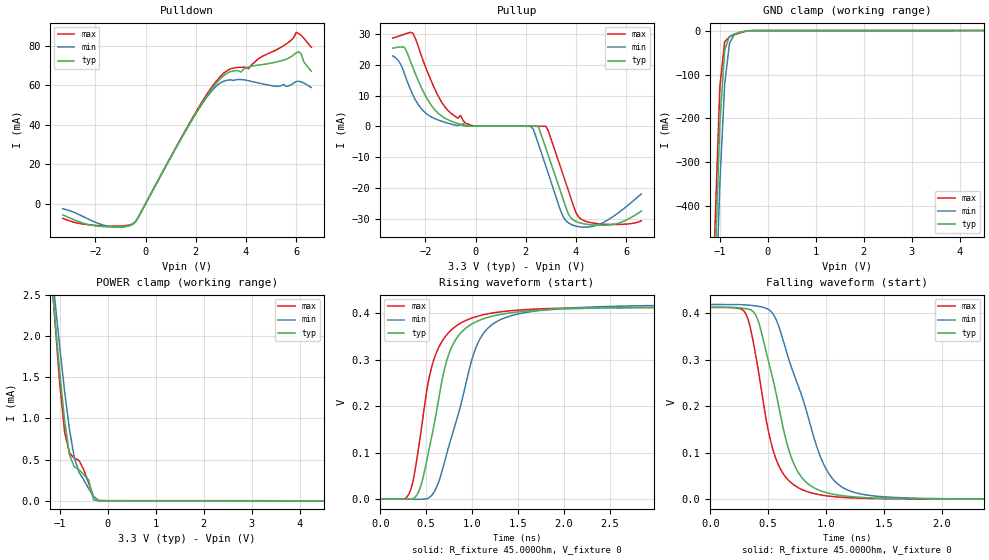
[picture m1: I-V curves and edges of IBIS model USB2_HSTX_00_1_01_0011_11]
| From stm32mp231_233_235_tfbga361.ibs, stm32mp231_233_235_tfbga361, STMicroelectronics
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[Model] USB2_HSTX_00_1_01_0011_11
Model_type   Output
Polarity   Non-Inverting
Enable   Active-High
C_comp   8.036pF   7.631pF   8.569pF
Vmeas = 200.000mV
Vref = 200.000mV
Rref = 45Ohms
Cref = 0pF
[Model Spec]
Vmeas   200.000mV   200.000mV   200.000mV
Vref   200.000mV   200.000mV   200.000mV
| This model is not intended for timing simulations.
| Warnings about Cref, Vref & Rref can be ignored
[Temperature Range]   25.000   125.000   -40.000
[Voltage Range]   3.300V   3.070V   3.630V
[GND Clamp Reference]   0.00V   0.00V   0.00V
[Pulldown Reference]   0.00V   0.00V   0.00V
[POWER Clamp Reference]   3.300V   3.070V   3.630V
[Pullup Reference]   3.300V   3.070V   3.630V
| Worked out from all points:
|   slope of the pulldown table from 0 to 0.495 V, typ, clamps not added: 42.6 ohm
|   GND clamp passes 1 mA (typ) near -0.43 V on its own axis
|   POWER clamp passes 1 mA (typ) near -0.91 V on its own axis
|   rising waveform, R_fixture 45.000Ohm, V_fixture 0: 20-80 % time 279ps typ, 356ps min, 250ps max; typ from 0 V to 0.413 V
|   falling waveform, R_fixture 45.000Ohm, V_fixture 0: 20-80 % time 241ps typ, 327ps min, 196ps max; typ from 0.413 V to 0 V
[GND Clamp]
-3.3V     -11.02A    -10.62A    -11.32A
-1.2V     -931.6mA   -1.049A    -855.7mA
-1.1V     -533.1mA   -671.7mA   -440.2mA
-1V       -209.4mA   -347mA     -127.3mA
-900mV    -44.44mA   -121.7mA   -25.6mA
-800mV    -13.15mA   -29.48mA   -14.15mA
-700mV    -7.742mA   -9.125mA   -9.769mA
-500mV    -2.127mA   -1.981mA   -2.894mA
-300mV    -19.36uA   -62.22uA   -13.54uA
6.6V      10.37uA    26.59uA    21.05uA
[Power Clamp]
-3.3V     3.206A     2.175A     4.855A
-1.2V     2.88mA     3.008mA    2.969mA
-1.1V     2.195mA    2.419mA    2.156mA
-1V       1.545mA    1.852mA    1.406mA
-900mV    967.9uA    1.324mA    831.4uA
-800mV    558.5uA    864.6uA    580.3uA
-700mV    412uA      525.9uA    517uA
-600mV    376.6uA    345uA      488.5uA
-400mV    254.2uA    146.6uA    216.8uA
-300mV    11.21uA    52.87uA    53.51uA
-100mV    94.79nA    985nA      361.1nA
6.6V      -3.252uA   -5.18uA    -3.94uA
[Pulldown]
-3.3V     -5.671mA   -2.581mA   -7.449mA
-1.6V     -11.64mA   -11.09mA   -11.31mA
-500mV    -10.25mA   -10.32mA   -10.1mA
1.9V      43.42mA    43.46mA    44.13mA
2.9V      62.15mA    60.37mA    63.26mA
3.4V      66.87mA    62.63mA    68.29mA
4.1V      69.19mA    62.19mA    68.26mA
4.5V      70.11mA    61.06mA    73.4mA
5.6V      73.12mA    59.29mA    80.76mA
6V        76.33mA    61.79mA    86.69mA
6.1V      76.87mA    61.92mA    85.99mA
6.6V      66.99mA    58.79mA    79.1mA
[Pullup]
-3.3V     25.41mA    22.86mA    28.67mA
-2.8V     25.3mA     16.38mA    30mA
-2.5V     19.22mA    10.28mA    30.28mA
-1.2V     2.602mA    1.31mA     6.11mA
-100mV    93.8uA     82.61uA    220.4uA
2.2V      68.59uA    -28.24uA   104.8uA
2.5V      -41.41uA   -5.658mA   83.48uA
2.9V      -9.472mA   -15.37mA   -1.562mA
3.5V      -23.92mA   -29.44mA   -16.02mA
3.8V      -29.68mA   -31.75mA   -23.35mA
4.4V      -31.68mA   -32.65mA   -30.79mA
6.6V      -27.44mA   -21.87mA   -30.62mA
[Ramp]
R_load=45.000Ohm
dV/dt_r   624.180mV/1.120ns  592.511mV/1.160ns  677.764mV/1.040ns
dV/dt_f   626.380mV/265.000ps  595.435mV/350.000ps  679.593mV/225.000ps
[Rising waveform]
R_fixture=45.000Ohm
V_fixture=0
0s        452.1nV    3.129uV    468.1nV
330ps     -200.2uV   -412.7uV   19.76mV
440ps     27.58mV    -306.8uV   140.7mV
580ps     153.8mV    13.3mV     298.1mV
780ps     328.2mV    136.1mV    365.5mV
1.01ns    378.6mV    308.3mV    390.9mV
1.14ns    389.5mV    360.9mV    397.8mV
1.51ns    403.4mV    399.1mV    407.2mV
2.38ns    411.4mV    414.3mV    412.4mV
9.9ns     413.1mV    419.2mV    412.9mV
[Falling waveform]
R_fixture=45.000Ohm
V_fixture=0
0s        412.6mV    418.6mV    412.3mV
310ps     409.6mV    417.6mV    396.7mV
410ps     385.7mV    414.9mV    283.8mV
540ps     258.8mV    398.9mV    107.3mV
650ps     130.9mV    323.5mV    48mV
720ps     76.94mV    269.7mV    31.23mV
960ps     17.56mV    85.72mV    9.103mV
1.17ns    6.864mV    21.76mV    3.734mV
1.65ns    1.442mV    3.396mV    968.9uV
9.9ns     13.76uV    30.59uV    4.187uV
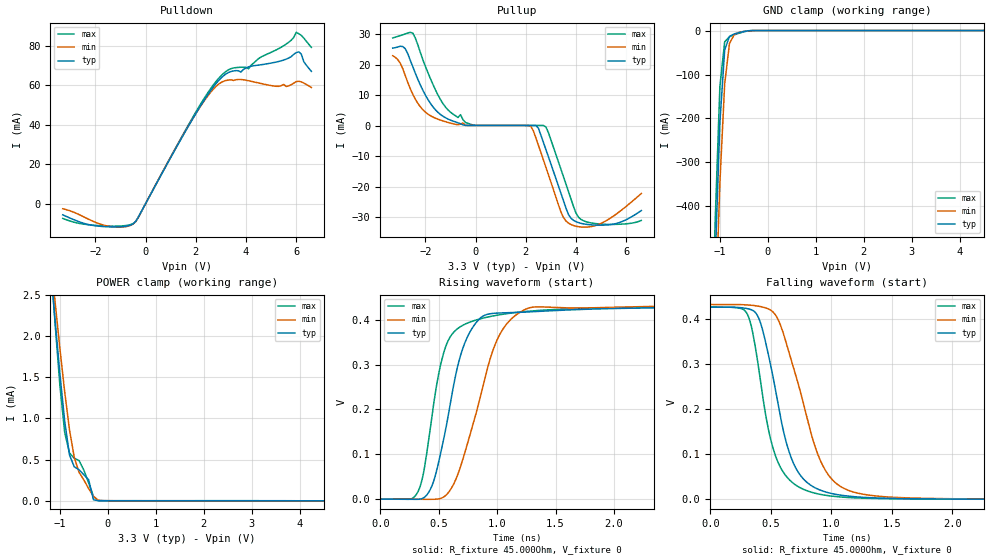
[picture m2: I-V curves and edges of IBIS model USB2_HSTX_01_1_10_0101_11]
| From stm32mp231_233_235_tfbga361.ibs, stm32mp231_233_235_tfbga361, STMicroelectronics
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[Model] USB2_HSTX_01_1_10_0101_11
Model_type   Output
Polarity   Non-Inverting
Enable   Active-High
C_comp   8.036pF   7.631pF   8.569pF
Vmeas = 200.000mV
Vref = 200.000mV
Rref = 45Ohms
Cref = 0pF
[Model Spec]
Vmeas   200.000mV   200.000mV   200.000mV
Vref   200.000mV   200.000mV   200.000mV
| This model is not intended for timing simulations.
| Warnings about Cref, Vref & Rref can be ignored
[Temperature Range]   25.000   125.000   -40.000
[Voltage Range]   3.300V   3.070V   3.630V
[GND Clamp Reference]   0.00V   0.00V   0.00V
[Pulldown Reference]   0.00V   0.00V   0.00V
[POWER Clamp Reference]   3.300V   3.070V   3.630V
[Pullup Reference]   3.300V   3.070V   3.630V
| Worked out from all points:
|   slope of the pulldown table from 0 to 0.495 V, typ, clamps not added: 42.6 ohm
|   GND clamp passes 1 mA (typ) near -0.43 V on its own axis
|   POWER clamp passes 1 mA (typ) near -0.91 V on its own axis
|   rising waveform, R_fixture 45.000Ohm, V_fixture 0: 20-80 % time 213ps typ, 282ps min, 175ps max; typ from 0 V to 0.428 V
|   falling waveform, R_fixture 45.000Ohm, V_fixture 0: 20-80 % time 215ps typ, 280ps min, 185ps max; typ from 0.427 V to 0 V
[GND Clamp]
-3.3V     -11.02A    -10.62A    -11.32A
-1.2V     -931.6mA   -1.049A    -855.7mA
-1.1V     -533.1mA   -671.7mA   -440.2mA
-1V       -209.4mA   -347mA     -127.3mA
-900mV    -44.44mA   -121.7mA   -25.6mA
-800mV    -13.15mA   -29.48mA   -14.15mA
-700mV    -7.743mA   -9.125mA   -9.769mA
-500mV    -2.127mA   -1.981mA   -2.894mA
-300mV    -19.51uA   -62.22uA   -13.7uA
6.6V      10.37uA    26.59uA    21.05uA
[Power Clamp]
-3.3V     3.206A     2.175A     4.855A
-1.2V     2.88mA     3.008mA    2.969mA
-1.1V     2.195mA    2.419mA    2.156mA
-1V       1.545mA    1.852mA    1.406mA
-900mV    967.6uA    1.324mA    831.4uA
-800mV    558uA      864.6uA    580.3uA
-700mV    412uA      525.9uA    517uA
-600mV    376.6uA    345uA      488.5uA
-400mV    254.2uA    146.6uA    216.8uA
-300mV    11.21uA    52.87uA    53.51uA
-100mV    94.86nA    985nA      361.1nA
6.6V      -2.538uA   -5.181uA   -3.292uA
[Pulldown]
-3.3V     -5.671mA   -2.581mA   -7.449mA
-1.6V     -11.64mA   -11.09mA   -11.31mA
-500mV    -10.25mA   -10.32mA   -10.1mA
1.9V      43.42mA    43.46mA    44.13mA
2.9V      62.15mA    60.37mA    63.26mA
3.4V      66.87mA    62.63mA    68.29mA
4.1V      69.19mA    62.19mA    68.26mA
4.5V      70.11mA    61.06mA    73.4mA
5.6V      73.12mA    59.29mA    80.76mA
6V        76.42mA    61.78mA    86.69mA
6.1V      76.81mA    61.92mA    85.99mA
6.6V      66.95mA    58.79mA    79.1mA
[Pullup]
-3.3V     25.37mA    22.87mA    28.68mA
-2.8V     25.17mA    16.38mA    30mA
-2.5V     19.29mA    10.28mA    30.28mA
-1.7V     6.185mA    2.83mA     13.54mA
-400mV    111.7uA    77.66uA    1.021mA
2.2V      68.64uA    -248.9uA   104.8uA
2.5V      -771uA     -6.354mA   83.49uA
2.8V      -7.784mA   -13.58mA   -409.6uA
3.4V      -22.12mA   -28.2mA    -14.26mA
3.8V      -30.28mA   -32.32mA   -24mA
4.4V      -32.24mA   -33.17mA   -31.39mA
6.6V      -27.75mA   -22.18mA   -30.98mA
[Ramp]
R_load=45.000Ohm
dV/dt_r   628.630mV/1.040ns  596.900mV/1.070ns  682.278mV/975.000ps
dV/dt_f   630.819mV/240.000ps  599.812mV/315.000ps  684.093mV/215.000ps
[Rising waveform]
R_fixture=45.000Ohm
V_fixture=0
0s        452.1nV    3.134uV    468nV
330ps     -314.7uV   -409uV     20.75mV
450ps     34.96mV    -426uV     199.2mV
520ps     106.6mV    1.896mV    303.6mV
590ps     198.7mV    17.05mV    357.8mV
730ps     352.3mV    109.3mV    390.5mV
940ps     413.1mV    312.6mV    406.9mV
1.09ns    415.3mV    393mV      413.6mV
1.33ns    418mV      428.4mV    420mV
9.9ns     427.9mV    433.7mV    427.8mV
[Falling waveform]
R_fixture=45.000Ohm
V_fixture=0
0s        427.4mV    433.2mV    427.3mV
310ps     423.7mV    432.1mV    409.5mV
410ps     396.3mV    428.9mV    273mV
540ps     241.5mV    409.4mV    95.77mV
620ps     134.7mV    354.7mV    53.93mV
700ps     73.04mV    281.9mV    32.9mV
950ps     16.63mV    65.01mV    9.092mV
1.17ns    6.339mV    17.32mV    3.566mV
1.69ns    1.222mV    2.704mV    870.2uV
9.9ns     14.12uV    30.82uV    4.572uV
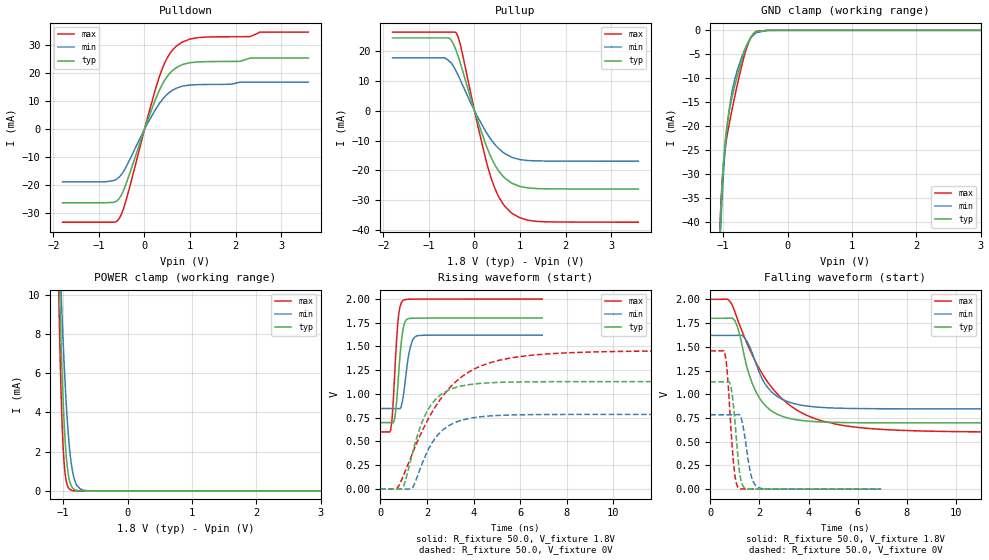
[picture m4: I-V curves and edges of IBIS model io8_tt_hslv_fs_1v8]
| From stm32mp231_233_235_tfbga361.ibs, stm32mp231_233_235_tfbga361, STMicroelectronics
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[Model]   io8_tt_hslv_fs_1v8
Model_type I/O
Polarity   Non-Inverting
Enable   Active-Low
| CAP_THRESHOLD on pad IOTT is "UDTCAPC" :
| Rising=30.0% of vddiov33m   Falling=70.0% of vddiov33m
| C_comp min and max val. don't necessarily correlate with the min and max pvt
| but are the smallest and greatest pad capacitance found.
| var   typ   min   max
C_comp   1.26692pF  1.09322pF  1.36434pF
|C_comp_pullup   869.30500fF  531.82500fF  521.20000fF
|C_comp_pulldown   397.61901fF  561.39543fF  843.14018fF
Vinl = 810.0mV
Vinh = 1.0V
Vmeas = 900.0mV   | Reference voltage for timing measurements
Cref  = 50.0pF   | Timing specification test load capacitance value
Rref  = 1.0MOhm   | Timing specification test load resistance value
Vref  = 990.0mV   | Timing specification test load voltage
[Model Spec]
| TIME_THRESHOLD on pin ZIV08M is "CMOS" :
| Rising=50.0% of vddv08m   Falling=50.0% of vddv08m
Vinl 675.70000mV 623.70000mV 735.70000mV
Vinh 1.12730V 1.01130V 1.24930V
| variable   typ   min   max
[Temperature Range] 25.0 125.0 -40.0
| variable   typ   min   max
[Voltage Range] 1.8V 1.62V 2.0V
| variable   typ   min   max
[POWER Clamp Reference] 1.8V 1.62V 2.0V
| variable   typ   min   max
[GND Clamp Reference] 0V 0V 0V
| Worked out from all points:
|   slope of the pulldown table from 0 to 0.27 V, typ, clamps not added: 22.9 ohm
|   slope of the pullup table from 0 to 0.27 V, typ, clamps not added: 22.2 ohm
|   GND clamp passes 1 mA (typ) near -0.55 V on its own axis
|   POWER clamp passes 1 mA (typ) near -0.93 V on its own axis
|   rising waveform, R_fixture 50.0, V_fixture 1.8V: 20-80 % time 218ps typ, 263ps min, 198ps max; typ from 0.698 V to 1.8 V
|   falling waveform, R_fixture 50.0, V_fixture 1.8V: 20-80 % time 878ps typ, 941ps min, 2.05ns max; typ from 1.8 V to 0.698 V
|   rising waveform, R_fixture 50.0, V_fixture 0V: 20-80 % time 1.01ns typ, 1.09ns min, 2.17ns max; typ from 0 V to 1.13 V
|   falling waveform, R_fixture 50.0, V_fixture 0V: 20-80 % time 237ps typ, 289ps min, 231ps max; typ from 1.13 V to 0 V
[POWER Clamp]
-1.8V     152.1mA    105.6mA    221.1mA
-1.07V    12.07mA    13.62mA    10.38mA
-1.05V    9.569mA    11.75mA    7.249mA
-1.03V    7.339mA    9.993mA    4.743mA
-1.01V    5.42mA     8.357mA    2.898mA
-990mV    3.841mA    6.859mA    1.662mA
-970mV    2.609mA    5.513mA    906.5uA
-940mV    1.358mA    3.806mA    344.1uA
-880mV    308.3uA    1.548mA    45.55uA
-790mV    28.47uA    298.6uA    2.144uA
-610mV    219.5nA    7.365uA    27.8nA
3.6V      0A         0A         0A
[GND Clamp]
-1.8V     -1.222A    -1.193A    -1.238A
-1.05V    -42.33mA   -45.55mA   -41.2mA
-1.04V    -38.89mA   -42.1mA    -37.88mA
-1.03V    -35.83mA   -38.98mA   -35.06mA
-1.01V    -30.7mA    -33.54mA   -30.61mA
-970mV    -23.47mA   -25.17mA   -24.97mA
-920mV    -18.06mA   -18.06mA   -20.63mA
-870mV    -14.51mA   -13.44mA   -17.13mA
-780mV    -9.532mA   -8.354mA   -11.38mA
-650mV    -3.743mA   -3.581mA   -4.327mA
-490mV    -324.1uA   -556uA     -259.6uA
3.6V      67.14nA    3.404uA    33.72nA
| variable   typ   min   max
[Pullup Reference] 1.8V 1.62V 2.0V
| variable   typ   min   max
[Pulldown Reference] 0V 0V 0V
[Pullup]
-1.8V     24.41mA    17.74mA    26.36mA
-680mV    24.41mA    17.73mA    26.36mA
-550mV    24.31mA    16.53mA    26.36mA
-400mV    20.04mA    13.14mA    26mA
-300mV    15.41mA    9.911mA    21.43mA
70mV      -3.39mA    -2.114mA   -4.868mA
340mV     -14.76mA   -9.139mA   -21.3mA
540mV     -20.33mA   -12.79mA   -29.04mA
810mV     -24.17mA   -15.52mA   -34.21mA
1V        -25.38mA   -16.37mA   -35.89mA
1.37V     -26.08mA   -16.81mA   -37.09mA
3.6V      -26.24mA   -16.92mA   -37.35mA
[Pulldown]
-1.8V     -26.25mA   -18.79mA   -33.2mA
-690mV    -26.13mA   -18.35mA   -33.2mA
-550mV    -24.6mA    -16.98mA   -31.75mA
-400mV    -19.26mA   -13.29mA   -25.07mA
70mV      3.286mA    2.202mA    4.389mA
320mV     13.66mA    9.041mA    18.43mA
500mV     18.91mA    12.52mA    25.54mA
700mV     22.05mA    14.7mA     29.73mA
1.18V     24.11mA    15.98mA    32.81mA
2.31V     25.4mA     16.88mA    33.16mA
2.54V     25.49mA    16.88mA    34.76mA
3.6V      25.49mA    16.88mA    34.76mA
[Ramp]
dV/dt_r 677.91633mV/1.00938ns 470.5214mV/1.08628ns 874.05215mV/2.1718ns
dV/dt_f 661.09817mV/874.73173ps 464.2591mV/938.08372ps 840.44947mV/2.05095ns
R_load = 50.0
| Removed startup time: 0s 0s 0s  .
| Removed end time: 6.95ns.
[Rising Waveform]
R_fixture   = 50.0
V_fixture   = 1.8V
V_fixture_min = 1.62V
V_fixture_max = 2.0V
0s        698.2mV    846.2mV    599.3mV
450ps     698.2mV    846.2mV    624.4mV
500ps     698.4mV    846.2mV    723.5mV
600ps     718.7mV    846.2mV    1.125V
750ps     1.074V     846.5mV    1.741V
850ps     1.416V     844.2mV    1.922V
1ns       1.71V      999.7mV    1.988V
1.25ns    1.796V     1.451V     1.998V
1.55ns    1.799V     1.61V      1.999V
6.95ns    1.8V       1.62V      2V
| Removed startup time: 0s 0s 0s  .
| Removed end time: 199.9ns.
[Falling Waveform]
R_fixture   = 50.0
V_fixture   = 1.8V
V_fixture_min = 1.62V
V_fixture_max = 2.0V
0s        1.8V       1.62V      2V
700ps     1.8V       1.62V      2.002V
1ns       1.774V     1.62V      1.87V
1.4ns     1.382V     1.593V     1.595V
1.8ns     1.057V     1.367V     1.364V
2.2ns     892.4mV    1.12V      1.18V
2.7ns     792.7mV    981.2mV    1.011V
4.7ns     706.3mV    858.5mV    708.5mV
8.6ns     698.3mV    846.4mV    612.9mV
199.9ns   698.2mV    846.2mV    599.3mV
| Removed startup time: 0s 0s 0s  .
| Removed end time: 199.9ns.
[Rising Waveform]
R_fixture   = 50.0
V_fixture   = 0V
V_fixture_min = 0V
V_fixture_max = 0V
0s        168.1nV    2.512uV    244.7nV
700ps     -3.16mV    -6.378uV   -1.166mV
1ns       26.06mV    -2.115mV   142.9mV
1.4ns     393.8mV    14.12mV    386.4mV
1.9ns     763.3mV    327.8mV    660.7mV
2.8ns     1.024V     642.6mV    1.015V
3.7ns     1.093V     735.4mV    1.216V
4.8ns     1.119V     769.3mV    1.335V
8.7ns     1.13V      783.9mV    1.439V
199.9ns   1.13V      784.2mV    1.457V
| Removed startup time: 0s 0s 0s  .
| Removed end time: 6.95ns.
[Falling Waveform]
R_fixture   = 50.0
V_fixture   = 0V
V_fixture_min = 0V
V_fixture_max = 0V
0s        1.13V      784.2mV    1.457V
600ps     1.13V      784.2mV    1.422V
700ps     1.13V      784.2mV    1.204V
850ps     1.064V     784.2mV    599.3mV
1ns       726.2mV    784mV      149mV
1.15ns    269mV      787.3mV    13.74mV
1.35ns    24.88mV    641.3mV    1.873mV
1.65ns    1.519mV    154.7mV    826.9uV
1.95ns    714.2uV    18.55mV    505.8uV
6.95ns    14.22uV    29.08uV    26.38uV
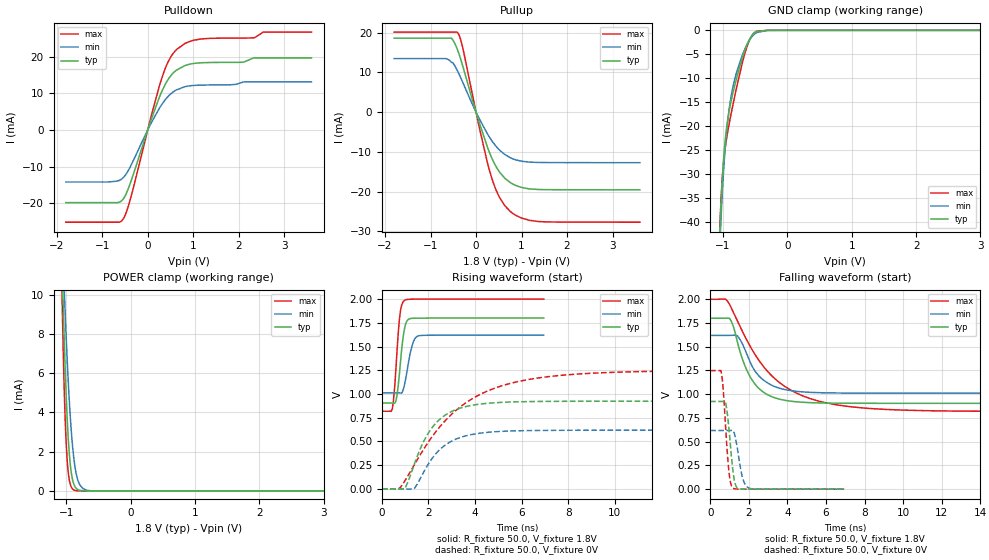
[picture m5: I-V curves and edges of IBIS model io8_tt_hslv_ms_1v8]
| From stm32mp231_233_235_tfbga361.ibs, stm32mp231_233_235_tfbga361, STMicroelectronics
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[Model]   io8_tt_hslv_ms_1v8
Model_type I/O
Polarity   Non-Inverting
Enable   Active-Low
| CAP_THRESHOLD on pad IOTT is "UDTCAPC" :
| Rising=30.0% of vddiov33m   Falling=70.0% of vddiov33m
| C_comp min and max val. don't necessarily correlate with the min and max pvt
| but are the smallest and greatest pad capacitance found.
| var   typ   min   max
C_comp   1.26676pF  1.09321pF  1.36432pF
|C_comp_pullup   869.30500fF  531.82000fF  521.19000fF
|C_comp_pulldown   397.45251fF  561.39043fF  843.12518fF
Vinl = 810.0mV
Vinh = 1.0V
Vmeas = 900.0mV   | Reference voltage for timing measurements
Cref  = 50.0pF   | Timing specification test load capacitance value
Rref  = 1.0MOhm   | Timing specification test load resistance value
Vref  = 990.0mV   | Timing specification test load voltage
[Model Spec]
| TIME_THRESHOLD on pin ZIV08M is "CMOS" :
| Rising=50.0% of vddv08m   Falling=50.0% of vddv08m
Vinl 675.70000mV 623.70000mV 735.70000mV
Vinh 1.12730V 1.01130V 1.24930V
| variable   typ   min   max
[Temperature Range] 25.0 125.0 -40.0
| variable   typ   min   max
[Voltage Range] 1.8V 1.62V 2.0V
| variable   typ   min   max
[POWER Clamp Reference] 1.8V 1.62V 2.0V
| variable   typ   min   max
[GND Clamp Reference] 0V 0V 0V
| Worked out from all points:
|   slope of the pulldown table from 0 to 0.27 V, typ, clamps not added: 28.9 ohm
|   slope of the pullup table from 0 to 0.27 V, typ, clamps not added: 28.7 ohm
|   GND clamp passes 1 mA (typ) near -0.55 V on its own axis
|   POWER clamp passes 1 mA (typ) near -0.93 V on its own axis
|   rising waveform, R_fixture 50.0, V_fixture 1.8V: 20-80 % time 226ps typ, 284ps min, 202ps max; typ from 0.904 V to 1.8 V
|   falling waveform, R_fixture 50.0, V_fixture 1.8V: 20-80 % time 1.09ns typ, 1.13ns min, 2.65ns max; typ from 1.8 V to 0.904 V
|   rising waveform, R_fixture 50.0, V_fixture 0V: 20-80 % time 1.23ns typ, 1.25ns min, 2.87ns max; typ from 0 V to 0.924 V
|   falling waveform, R_fixture 50.0, V_fixture 0V: 20-80 % time 264ps typ, 319ps min, 248ps max; typ from 0.924 V to 0 V
[POWER Clamp]
-1.8V     152.1mA    105.6mA    221.1mA
-1.07V    12.07mA    13.62mA    10.38mA
-1.05V    9.569mA    11.75mA    7.249mA
-1.03V    7.339mA    9.993mA    4.743mA
-1.01V    5.42mA     8.357mA    2.898mA
-990mV    3.841mA    6.859mA    1.662mA
-970mV    2.609mA    5.513mA    906.5uA
-940mV    1.358mA    3.806mA    344.1uA
-880mV    308.3uA    1.548mA    45.55uA
-790mV    28.47uA    298.6uA    2.144uA
-610mV    219.5nA    7.365uA    27.8nA
3.6V      0A         0A         0A
[GND Clamp]
-1.8V     -1.222A    -1.193A    -1.238A
-1.05V    -42.33mA   -45.55mA   -41.2mA
-1.04V    -38.89mA   -42.1mA    -37.88mA
-1.03V    -35.83mA   -38.98mA   -35.06mA
-1.01V    -30.7mA    -33.54mA   -30.61mA
-970mV    -23.47mA   -25.17mA   -24.97mA
-920mV    -18.06mA   -18.06mA   -20.63mA
-870mV    -14.51mA   -13.44mA   -17.13mA
-780mV    -9.532mA   -8.354mA   -11.38mA
-650mV    -3.743mA   -3.581mA   -4.327mA
-490mV    -324.1uA   -556uA     -259.6uA
3.6V      67.14nA    3.404uA    33.72nA
| variable   typ   min   max
[Pullup Reference] 1.8V 1.62V 2.0V
| variable   typ   min   max
[Pulldown Reference] 0V 0V 0V
[Pullup]
-1.8V     18.62mA    13.47mA    20.14mA
-670mV    18.62mA    13.46mA    20.14mA
-550mV    18.62mA    12.65mA    20.14mA
-480mV    17.57mA    11.91mA    20.14mA
-390mV    15.13mA    9.968mA    19.73mA
-290mV    11.53mA    7.43mA     16.05mA
70mV      -2.634mA   -1.643mA   -3.782mA
330mV     -11.11mA   -6.899mA   -16mA
520mV     -15.13mA   -9.584mA   -21.53mA
810mV     -18.11mA   -11.75mA   -25.5mA
1.37V     -19.46mA   -12.66mA   -27.52mA
3.6V      -19.55mA   -12.72mA   -27.69mA
[Pulldown]
-1.8V     -19.85mA   -14.22mA   -25.2mA
-680mV    -19.85mA   -13.99mA   -25.2mA
-540mV    -18.89mA   -13.07mA   -24.34mA
-390mV    -14.81mA   -10.24mA   -19.27mA
300mV     10.22mA    6.776mA    13.77mA
460mV     14.01mA    9.309mA    18.88mA
630mV     16.33mA    10.94mA    21.94mA
1.18V     18.38mA    12.27mA    24.89mA
2.1V      18.52mA    13.1mA     25.11mA
2.31V     19.6mA     13.12mA    25.16mA
2.54V     19.69mA    13.12mA    26.75mA
3.6V      19.69mA    13.12mA    26.75mA
[Ramp]
dV/dt_r 554.12598mV/1.22814ns 370.82875mV/1.25117ns 749.30435mV/2.86537ns
dV/dt_f 537.59499mV/1.08996ns 365.35691mV/1.12832ns 709.23786mV/2.65093ns
R_load = 50.0
| Removed startup time: 0s 0s 0s  .
| Removed end time: 6.95ns.
[Rising Waveform]
R_fixture   = 50.0
V_fixture   = 1.8V
V_fixture_min = 1.62V
V_fixture_max = 2.0V
0s        904mV      1.011V     817.9mV
450ps     904mV      1.011V     844.3mV
600ps     922.8mV    1.011V     1.253V
750ps     1.203V     1.011V     1.78V
850ps     1.469V     1.01V      1.936V
950ps     1.661V     1.073V     1.982V
1.1ns     1.777V     1.269V     1.996V
1.3ns     1.797V     1.511V     1.999V
1.55ns    1.799V     1.61V      1.999V
6.95ns    1.8V       1.62V      2V
| Removed startup time: 0s 0s 0s  .
| Removed end time: 399.9ns.
[Falling Waveform]
R_fixture   = 50.0
V_fixture   = 1.8V
V_fixture_min = 1.62V
V_fixture_max = 2.0V
0s        1.8V       1.62V      2V
1ns       1.8V       1.62V      1.947V
1.4ns     1.559V     1.617V     1.777V
2ns       1.21V      1.372V     1.531V
2.5ns     1.066V     1.199V     1.363V
3.2ns     973.2mV    1.093V     1.192V
4.4ns     921.5mV    1.032V     1.019V
6ns       907mV      1.015V     909.4mV
11.6ns    904mV      1.011V     825.3mV
399.9ns   904mV      1.011V     817.9mV
| Removed startup time: 0s 0s 0s  .
| Removed end time: 399.9ns.
[Rising Waveform]
R_fixture   = 50.0
V_fixture   = 0V
V_fixture_min = 0V
V_fixture_max = 0V
0s        196.8nV    2.875uV    288.1nV
700ps     -2.264mV   -4.532uV   -1.554mV
1ns       8.351mV    -1.533mV   89.8mV
1.4ns     264.3mV    4.734mV    256.2mV
2.1ns     626.9mV    300.8mV    530.5mV
3.4ns     853.5mV    544.1mV    870.2mV
4.7ns     905mV      599.1mV    1.048V
6.3ns     919.6mV    614.2mV    1.153V
12.3ns    923.5mV    618mV      1.241V
399.9ns   923.5mV    618.1mV    1.249V
| Removed startup time: 0s 0s 0s  .
| Removed end time: 6.95ns.
[Falling Waveform]
R_fixture   = 50.0
V_fixture   = 0V
V_fixture_min = 0V
V_fixture_max = 0V
0s        923.5mV    618.1mV    1.249V
600ps     923.5mV    618mV      1.205V
700ps     923.8mV    618.1mV    980.6mV
850ps     854.2mV    618.1mV    490.5mV
1ns       571.7mV    617.9mV    133.2mV
1.15ns    241.5mV    620.7mV    17.21mV
1.35ns    26.99mV    498.3mV    2.167mV
1.65ns    1.582mV    140.5mV    862.1uV
2ns       678.2uV    12.95mV    480.5uV
6.95ns    16.65uV    33.24uV    31.33uV
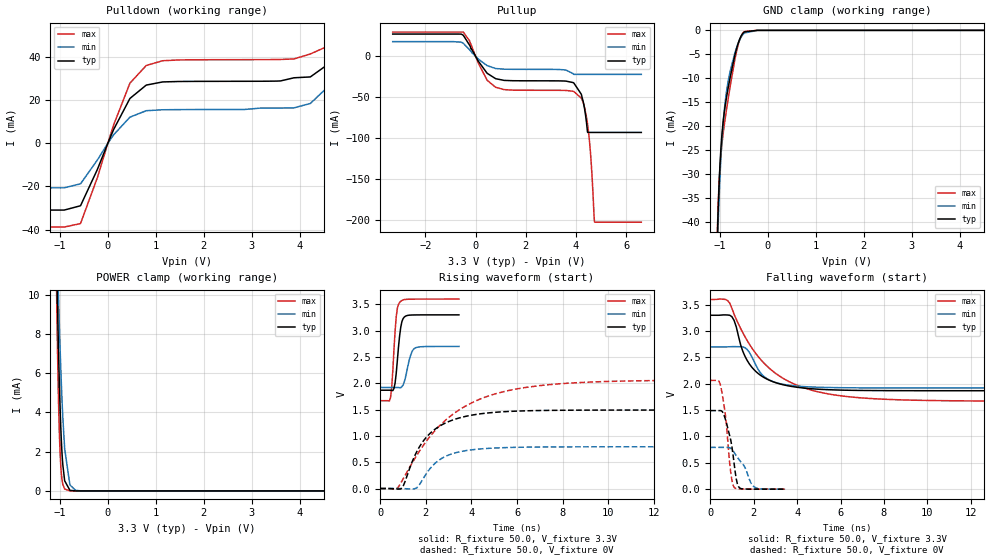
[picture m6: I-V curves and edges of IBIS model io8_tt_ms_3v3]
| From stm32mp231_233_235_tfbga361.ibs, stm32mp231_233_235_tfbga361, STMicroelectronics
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[Model]   io8_tt_ms_3v3
Model_type I/O
Polarity   Non-Inverting
Enable   Active-Low
| CAP_THRESHOLD on pad IOTT is "UDTCAPC" :
| Rising=30.0% of vddiov33m   Falling=70.0% of vddiov33m
| C_comp min and max val. don't necessarily correlate with the min and max pvt
| but are the smallest and greatest pad capacitance found.
| var   typ   min   max
C_comp   1.01860pF  1.01058pF  1.02128pF
|C_comp_pullup   495.66000fF  479.35500fF  510.70500fF
|C_comp_pulldown   522.94000fF  531.22429fF  510.57500fF
Vinl = 1.35V
Vinh = 1.8V
Vmeas = 1.65V   | Reference voltage for timing measurements
Cref  = 50.0pF   | Timing specification test load capacitance value
Rref  = 1.0MOhm   | Timing specification test load resistance value
Vref  = 1.815V   | Timing specification test load voltage
[Model Spec]
| TIME_THRESHOLD on pin ZIV08M is "CMOS" :
| Rising=50.0% of vddv08m   Falling=50.0% of vddv08m
Vinl 1.08570V 868.70000mV 1.21270V
Vinh 1.55630V 1.26230V 1.70930V
| variable   typ   min   max
[Temperature Range] 25.0 125.0 -40.0
| variable   typ   min   max
[Voltage Range] 3.3V 2.7V 3.6V
| variable   typ   min   max
[POWER Clamp Reference] 3.3V 2.7V 3.6V
| variable   typ   min   max
[GND Clamp Reference] 0V 0V 0V
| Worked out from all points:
|   slope of the pulldown table from 0 to 0.495 V, typ, clamps not added: 23.2 ohm
|   slope of the pullup table from 0 to 0.495 V, typ, clamps not added: 23.2 ohm
|   GND clamp passes 1 mA (typ) near -0.55 V on its own axis
|   POWER clamp passes 1 mA (typ) near -0.92 V on its own axis
|   rising waveform, R_fixture 50.0, V_fixture 3.3V: 20-80 % time 193ps typ, 257ps min, 169ps max; typ from 1.87 V to 3.3 V
|   falling waveform, R_fixture 50.0, V_fixture 3.3V: 20-80 % time 1.1ns typ, 830ps min, 2.35ns max; typ from 3.3 V to 1.87 V
|   rising waveform, R_fixture 50.0, V_fixture 0V: 20-80 % time 1.41ns typ, 1.15ns min, 2.82ns max; typ from 0 V to 1.49 V
|   falling waveform, R_fixture 50.0, V_fixture 0V: 20-80 % time 374ps typ, 631ps min, 305ps max; typ from 1.49 V to 0 V
[POWER Clamp]
-3.3V     1.353A     318.4mA    2.015A
-1.07V    12.07mA    13.62mA    10.38mA
-1.06V    10.79mA    12.68mA    8.745mA
-1.05V    9.571mA    11.76mA    7.253mA
-1.03V    7.341mA    9.999mA    4.748mA
-1V       4.588mA    7.595mA    2.215mA
-980mV    3.183mA    6.171mA    1.238mA
-950mV    1.704mA    4.337mA    481.8uA
-900mV    515.5uA    2.141mA    93.34uA
-790mV    29.45uA    301.7uA    4.884uA
-670mV    1.871uA    28.97uA    2.19uA
6.6V      0A         0A         0A
[GND Clamp]
-3.3V     -3.772A    -3.743A    -3.788A
-1.05V    -42.34mA   -45.44mA   -41.2mA
-1.04V    -38.9mA    -42mA      -37.88mA
-1.03V    -35.84mA   -38.88mA   -35.06mA
-1V       -28.57mA   -31.07mA   -28.88mA
-970mV    -23.48mA   -25.09mA   -24.97mA
-920mV    -18.07mA   -17.99mA   -20.63mA
-860mV    -13.91mA   -12.68mA   -16.46mA
-780mV    -9.536mA   -8.318mA   -11.38mA
-650mV    -3.744mA   -3.567mA   -4.327mA
-490mV    -324.2uA   -555.2uA   -259.7uA
6.6V      214nA      4.276uA    223.3nA
| variable   typ   min   max
[Pullup Reference] 3.3V 2.7V 3.6V
| variable   typ   min   max
[Pulldown Reference] 0V 0V 0V
[Pullup]
-3.3V     27.2mA     17.98mA    29.59mA
-490mV    25.74mA    15.97mA    29.59mA
460mV     -20.66mA   -11.32mA   -29.13mA
800mV     -27.28mA   -14.86mA   -37.8mA
3.91V     -32.42mA   -22.01mA   -42.86mA
4.21V     -46.23mA   -22.01mA   -50.96mA
4.33V     -62.19mA   -22.01mA   -61.25mA
4.43V     -84.61mA   -22.01mA   -76.93mA
4.46V     -92.6mA    -22.01mA   -83.09mA
4.58V     -92.85mA   -22.01mA   -119.7mA
4.74V     -92.85mA   -22.01mA   -202.4mA
6.6V      -92.85mA   -22.01mA   -202.4mA
[Pulldown]
-3.3V     -30.95mA   -20.65mA   -38.82mA
-570mV    -28.95mA   -18.8mA    -37.2mA
-220mV    -12.23mA   -7.828mA   -16.04mA
120mV     6.335mA    3.893mA    8.43mA
460mV     20.73mA    12.07mA    27.81mA
800mV     26.92mA    15.05mA    35.98mA
3.88V     30.3mA     16.38mA    39.04mA
4.22V     30.7mA     18.4mA     41.32mA
4.56V     36.08mA    25.54mA    44.69mA
4.9V      54.47mA    48.34mA    60.15mA
5.24V     110.5mA    112.9mA    109.4mA
6.6V      684.6mA    689.2mA    626.6mA
[Ramp]
dV/dt_r 894.61125mV/1.41225ns 475.7361mV/1.14756ns 1.23807V/2.82126ns
dV/dt_f 859.27473mV/1.09955ns 467.96348mV/827.73741ps 1.15858V/2.3539ns
R_load = 50.0
| Removed startup time: 0s 0s 0s  .
| Removed end time: 3.45ns.
[Rising Waveform]
R_fixture   = 50.0
V_fixture   = 3.3V
V_fixture_min = 2.7V
V_fixture_max = 3.6V
0s        1.868V     1.92V      1.669V
450ps     1.868V     1.92V      1.73V
500ps     1.866V     1.92V      1.917V
600ps     1.901V     1.92V      2.636V
700ps     2.19V      1.92V      3.263V
850ps     2.906V     1.916V     3.535V
1ns       3.227V     1.967V     3.583V
1.3ns     3.295V     2.487V     3.597V
1.5ns     3.298V     2.663V     3.598V
3.45ns    3.3V       2.7V       3.6V
| Removed startup time: 0s 0s 0s  .
| Removed end time: 24.9ns.
[Falling Waveform]
R_fixture   = 50.0
V_fixture   = 3.3V
V_fixture_min = 2.7V
V_fixture_max = 3.6V
0s        3.3V       2.7V       3.6V
700ps     3.307V     2.7V       3.6V
1ns       3.271V     2.705V     3.429V
1.6ns     2.52V      2.684V     2.892V
1.9ns     2.321V     2.523V     2.688V
2.4ns     2.137V     2.166V     2.424V
3.6ns     1.96V      1.974V     2.047V
5.3ns     1.89V      1.931V     1.818V
9.8ns     1.868V     1.92V      1.685V
24.9ns    1.868V     1.92V      1.669V
| Removed startup time: 0s 0s 0s  .
| Removed end time: 24.9ns.
[Rising Waveform]
R_fixture   = 50.0
V_fixture   = 0V
V_fixture_min = 0V
V_fixture_max = 0V
0s        423.2nV    2.439uV    509.8nV
700ps     -7.512mV   -132.9uV   -9.836mV
900ps     -9.015mV   -1.718mV   103mV
1.5ns     610.2mV    -5.575mV   559.3mV
1.8ns     847.9mV    128.4mV    763.5mV
2.7ns     1.21V      573.7mV    1.233V
4.1ns     1.4V       739.7mV    1.646V
5.9ns     1.469V     782.1mV    1.885V
10.6ns    1.491V     792.7mV    2.041V
24.9ns    1.491V     792.9mV    2.063V
| Removed startup time: 0s 0s 0s  .
| Removed end time: 3.45ns.
[Falling Waveform]
R_fixture   = 50.0
V_fixture   = 0V
V_fixture_min = 0V
V_fixture_max = 0V
0s        1.491V     792.9mV    2.064V
400ps     1.491V     792.9mV    2.049V
500ps     1.489V     792.9mV    1.917V
700ps     1.323V     793mV      1.396V
950ps     917.5mV    772.2mV    294.8mV
1.1ns     480mV      697.2mV    34.26mV
1.25ns    100.1mV    604.1mV    6.307mV
1.4ns     12.77mV    521.8mV    2.768mV
2.05ns    787.4uV    35.85mV    851.4uV
3.45ns    205.5uV    211.8uV    255.4uV
